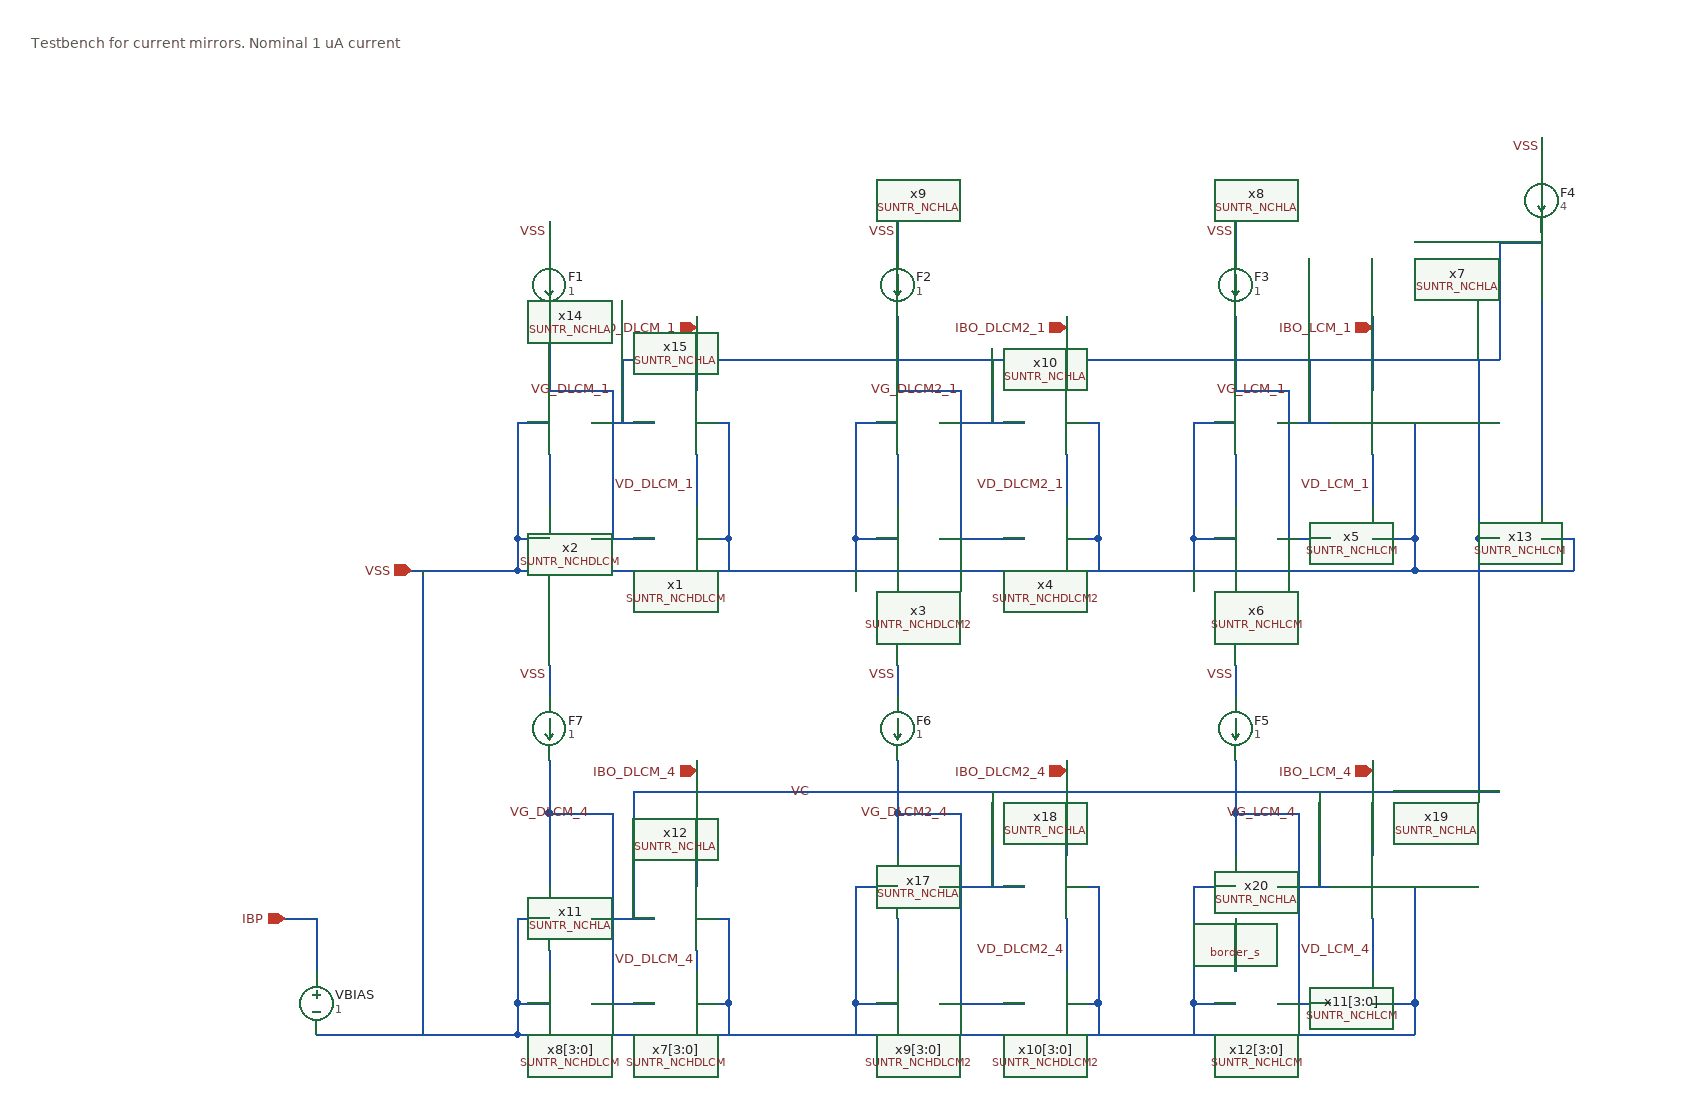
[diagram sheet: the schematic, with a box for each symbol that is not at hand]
v {xschem version=3.0.0 file_version=1.2 }
G {}
K {}
V {}
S {}
E {}
T {Testbench for current mirrors. Nominal 1 uA current} -580 -510 0 0 0.4 0.4 {}
N -120 -30 -90 -30 {
lab=VSS}
N -120 -30 -120 0 {
lab=VSS}
N -120 0 -90 -0 {
lab=VSS}
N -90 -0 50 0 {
lab=VSS}
N 50 0 240 0 {
lab=VSS}
N 200 -30 240 -30 {
lab=VSS}
N 200 -30 200 -0 {
lab=VSS}
N 50 -30 80 -30 {
lab=VSS}
N 80 -30 80 -0 {
lab=VSS}
N 240 0 400 0 {
lab=VSS}
N 400 0 560 0 {
lab=VSS}
N 560 0 690 0 {
lab=VSS}
N 520 -30 560 -30 {
lab=VSS}
N 520 -30 520 -0 {
lab=VSS}
N 400 -30 430 -30 {
lab=VSS}
N 430 -30 430 -0 {
lab=VSS}
N 280 -30 360 -30 {
lab=VG_DLCM2_1}
N 600 -30 650 -30 {
lab=VG_LCM_1}
N -50 -30 10 -30 {
lab=VG_DLCM_1}
N -220 0 -120 0 {
lab=VSS}
N -90 -110 -90 -60 {
lab=#net1}
N -90 -330 -90 -300 {
lab=VSS}
N 240 -110 240 -60 {
lab=#net2}
N 240 -330 240 -300 {
lab=VSS}
N 560 -110 560 -60 {
lab=#net3}
N 560 -330 560 -300 {
lab=VSS}
N 50 -110 50 -60 {
lab=VD_DLCM_1}
N 400 -110 400 -60 {
lab=VD_DLCM2_1}
N 690 -110 690 -60 {
lab=VD_LCM_1}
N 690 -30 730 -30 {
lab=VSS}
N 730 -30 730 -0 {
lab=VSS}
N 690 0 730 -0 {
lab=VSS}
N -120 410 -90 410 {
lab=VSS}
N -120 410 -120 440 {
lab=VSS}
N -120 440 -90 440 {
lab=VSS}
N -90 440 50 440 {
lab=VSS}
N 50 440 240 440 {
lab=VSS}
N 200 410 240 410 {
lab=VSS}
N 200 410 200 440 {
lab=VSS}
N 50 410 80 410 {
lab=VSS}
N 80 410 80 440 {
lab=VSS}
N 240 440 400 440 {
lab=VSS}
N 400 440 560 440 {
lab=VSS}
N 560 440 690 440 {
lab=VSS}
N 520 410 560 410 {
lab=VSS}
N 520 410 520 440 {
lab=VSS}
N 400 410 430 410 {
lab=VSS}
N 430 410 430 440 {
lab=VSS}
N 280 410 360 410 {
lab=VG_DLCM2_4}
N 300 380 300 410 {
lab=VG_DLCM2_4}
N 240 230 280 230 {
lab=VG_DLCM2_4}
N 600 410 650 410 {
lab=VG_LCM_4}
N 620 380 620 410 {
lab=VG_LCM_4}
N 560 230 600 230 {
lab=VG_LCM_4}
N -50 410 10 410 {
lab=VG_DLCM_4}
N -30 380 -30 410 {
lab=VG_DLCM_4}
N -90 230 -50 230 {
lab=VG_DLCM_4}
N -220 440 -120 440 {
lab=VSS}
N -90 180 -90 230 {
lab=VG_DLCM_4}
N -90 90 -90 120 {
lab=VSS}
N 240 180 240 230 {
lab=VG_DLCM2_4}
N 240 90 240 120 {
lab=VSS}
N 560 180 560 230 {
lab=VG_LCM_4}
N 560 90 560 120 {
lab=VSS}
N 50 180 50 230 {
lab=IBO_DLCM_4}
N 400 180 400 230 {
lab=IBO_DLCM2_4}
N 690 180 690 230 {
lab=IBO_LCM_4}
N 690 410 730 410 {
lab=VSS}
N 730 410 730 440 {
lab=VSS}
N 690 440 730 440 {
lab=VSS}
N -310 330 -310 380 {
lab=IBP}
N -340 330 -310 330 {
lab=IBP}
N -210 0 -210 440 {
lab=VSS}
N 600 -140 650 -140 {
lab=VC}
N 520 -140 560 -140 {
lab=VSS}
N 520 -140 520 -30 {
lab=VSS}
N 690 -140 730 -140 {
lab=VSS}
N 730 -140 730 -30 {
lab=VSS}
N -50 -140 10 -140 {
lab=VC}
N -120 -140 -90 -140 {
lab=VSS}
N -120 -140 -120 -30 {
lab=VSS}
N 50 -140 80 -140 {
lab=VSS}
N 80 -140 80 -30 {
lab=VSS}
N 200 -140 240 -140 {
lab=VSS}
N 200 -140 200 -30 {
lab=VSS}
N 400 -140 430 -140 {
lab=VSS}
N 430 -140 430 -30 {
lab=VSS}
N 280 -140 360 -140 {
lab=VC}
N -90 -170 -30 -170 {
lab=VG_DLCM_1}
N -30 -170 -30 -30 {
lab=VG_DLCM_1}
N 240 -170 300 -170 {
lab=VG_DLCM2_1}
N 300 -170 300 -30 {
lab=VG_DLCM2_1}
N 560 -170 610 -170 {
lab=VG_LCM_1}
N 610 -170 610 -30 {
lab=VG_LCM_1}
N 690 -240 690 -170 {
lab=IBO_LCM_1}
N 560 -240 560 -170 {
lab=VG_LCM_1}
N 400 -240 400 -170 {
lab=IBO_DLCM2_1}
N 240 -240 240 -170 {
lab=VG_DLCM2_1}
N 50 -240 50 -170 {
lab=IBO_DLCM_1}
N -90 -240 -90 -170 {
lab=VG_DLCM_1}
N 850 -410 850 -380 {
lab=VSS}
N 850 -30 880 -30 {
lab=VSS}
N 880 -30 880 -0 {
lab=VSS}
N 850 -0 880 -0 {
lab=VSS}
N 730 0 850 -0 {
lab=VSS}
N -20 -200 -20 -140 {
lab=VC}
N -20 -200 800 -200 {
lab=VC}
N 330 -200 330 -140 {
lab=VC}
N 630 -200 630 -140 {
lab=VC}
N 790 -200 790 -30 {
lab=VC}
N 800 -200 810 -200 {
lab=VC}
N 810 -270 810 -200 {
lab=VC}
N 850 -320 850 -300 {
lab=VC}
N 810 -310 810 -270 {
lab=VC}
N 810 -310 850 -310 {
lab=VC}
N 240 330 240 380 {
lab=#net4}
N 400 330 400 380 {
lab=VD_DLCM2_4}
N 200 300 240 300 {
lab=VSS}
N 200 300 200 410 {
lab=VSS}
N 400 300 430 300 {
lab=VSS}
N 430 300 430 410 {
lab=VSS}
N 280 300 360 300 {
lab=VC}
N 560 330 560 380 {
lab=#net5}
N 690 330 690 380 {
lab=VD_LCM_4}
N 600 300 650 300 {
lab=VC}
N 520 300 560 300 {
lab=VSS}
N 520 300 520 410 {
lab=VSS}
N 690 300 730 300 {
lab=VSS}
N 730 300 730 410 {
lab=VSS}
N -90 360 -90 380 {
lab=#net6}
N 50 360 50 380 {
lab=VD_DLCM_4}
N 50 330 80 330 {
lab=VSS}
N 80 330 80 410 {
lab=VSS}
N -120 330 -90 330 {
lab=VSS}
N -120 330 -120 410 {
lab=VSS}
N -90 230 -90 300 {
lab=VG_DLCM_4}
N -50 330 10 330 {
lab=VC}
N -30 230 -30 380 {
lab=VG_DLCM_4}
N -50 230 -30 230 {
lab=VG_DLCM_4}
N 50 230 50 300 {
lab=IBO_DLCM_4}
N 240 230 240 270 {
lab=VG_DLCM2_4}
N 300 230 300 380 {
lab=VG_DLCM2_4}
N 280 230 300 230 {
lab=VG_DLCM2_4}
N 400 230 400 270 {
lab=IBO_DLCM2_4}
N 620 230 620 380 {
lab=VG_LCM_4}
N 600 230 620 230 {
lab=VG_LCM_4}
N 560 230 560 270 {
lab=VG_LCM_4}
N 690 230 690 270 {
lab=IBO_LCM_4}
N -10 210 -10 330 {
lab=VC}
N -10 210 810 210 {
lab=VC}
N 790 -30 790 210 {
lab=VC}
N 640 210 640 300 {
lab=VC}
N 330 210 330 300 {
lab=VC}
N 850 -300 850 -220 {
lab=VC}
N 850 -220 850 -60 {
lab=VC}
N 790 -30 810 -30 {
lab=VC}
N -310 440 -220 440 {
lab=VSS}
C {SUN_TR_SKY130NM/SUNTR_NCHDLCM.sym} 10 -30 0 0 {name=x1 }
C {SUN_TR_SKY130NM/SUNTR_NCHDLCM.sym} -50 -30 0 1 {name=x2 }
C {SUN_TR_SKY130NM/SUNTR_NCHDLCM2.sym} 280 -30 0 1 {name=x3 }
C {SUN_TR_SKY130NM/SUNTR_NCHDLCM2.sym} 360 -30 0 0 {name=x4 }
C {SUN_TR_SKY130NM/SUNTR_NCHLCM.sym} 650 -30 0 0 {name=x5 }
C {SUN_TR_SKY130NM/SUNTR_NCHLCM.sym} 600 -30 0 1 {name=x6 }
C {devices/ipin.sym} -220 0 0 0 {name=p1 lab=VSS}
C {devices/lab_wire.sym} -90 -320 0 0 {name=l1 sig_type=std_logic lab=VSS}
C {devices/lab_wire.sym} 240 -320 0 0 {name=l2 sig_type=std_logic lab=VSS}
C {devices/lab_wire.sym} 560 -320 0 0 {name=l3 sig_type=std_logic lab=VSS}
C {devices/ipin.sym} 50 -230 1 0 {name=p2 lab=IBO_DLCM_1}
C {devices/ipin.sym} 400 -230 1 0 {name=p3 lab=IBO_DLCM2_1}
C {devices/ipin.sym} 690 -230 1 0 {name=p4 lab=IBO_LCM_1}
C {SUN_TR_SKY130NM/SUNTR_NCHDLCM.sym} 10 410 0 0 {name=x7[3:0]}
C {SUN_TR_SKY130NM/SUNTR_NCHDLCM.sym} -50 410 0 1 {name=x8[3:0]}
C {SUN_TR_SKY130NM/SUNTR_NCHDLCM2.sym} 280 410 0 1 {name=x9[3:0]}
C {SUN_TR_SKY130NM/SUNTR_NCHDLCM2.sym} 360 410 0 0 {name=x10[3:0]}
C {SUN_TR_SKY130NM/SUNTR_NCHLCM.sym} 650 410 0 0 {name=x11[3:0]}
C {SUN_TR_SKY130NM/SUNTR_NCHLCM.sym} 600 410 0 1 {name=x12[3:0]}
C {devices/lab_wire.sym} -90 100 0 0 {name=l4 sig_type=std_logic lab=VSS}
C {devices/lab_wire.sym} 240 100 0 0 {name=l5 sig_type=std_logic lab=VSS}
C {devices/lab_wire.sym} 560 100 0 0 {name=l6 sig_type=std_logic lab=VSS}
C {devices/ipin.sym} 50 190 1 0 {name=p6 lab=IBO_DLCM_4}
C {devices/ipin.sym} 400 190 1 0 {name=p7 lab=IBO_DLCM2_4}
C {devices/ipin.sym} 690 190 1 0 {name=p8 lab=IBO_LCM_4}
C {devices/cccs.sym} -90 -270 0 0 {name=F1 vnam=VBIAS value=1}
C {devices/vsource.sym} -310 410 0 0 {name=VBIAS value=1}
C {devices/cccs.sym} 240 -270 0 0 {name=F2 vnam=VBIAS value=1}
C {devices/cccs.sym} 560 -270 0 0 {name=F3 vnam=VBIAS value=1}
C {devices/cccs.sym} 560 150 0 0 {name=F5 vnam=VBIAS value=1}
C {devices/cccs.sym} 240 150 0 0 {name=F6 vnam=VBIAS value=1}
C {devices/cccs.sym} -90 150 0 0 {name=F7 vnam=VBIAS value=1}
C {devices/ipin.sym} -340 330 0 0 {name=p9 lab=IBP}
C {cborder/border_s.sym} 580 360 0 0 {}
C {SUN_TR_SKY130NM/SUNTR_NCHLA.sym} 650 -140 0 0 {name=x7 }
C {SUN_TR_SKY130NM/SUNTR_NCHLA.sym} 600 -140 0 1 {name=x8 }
C {SUN_TR_SKY130NM/SUNTR_NCHLA.sym} 280 -140 0 1 {name=x9 }
C {SUN_TR_SKY130NM/SUNTR_NCHLA.sym} 360 -140 0 0 {name=x10 }
C {SUN_TR_SKY130NM/SUNTR_NCHLA.sym} -50 330 0 1 {name=x11 }
C {SUN_TR_SKY130NM/SUNTR_NCHLA.sym} 10 330 0 0 {name=x12 }
C {devices/lab_wire.sym} 850 -400 0 0 {name=l7 sig_type=std_logic lab=VSS}
C {devices/cccs.sym} 850 -350 0 0 {name=F4 vnam=VBIAS value=4}
C {SUN_TR_SKY130NM/SUNTR_NCHLCM.sym} 810 -30 0 0 {name=x13 }
C {SUN_TR_SKY130NM/SUNTR_NCHLA.sym} 280 300 0 1 {name=x17 }
C {SUN_TR_SKY130NM/SUNTR_NCHLA.sym} 360 300 0 0 {name=x18 }
C {SUN_TR_SKY130NM/SUNTR_NCHLA.sym} 650 300 0 0 {name=x19 }
C {SUN_TR_SKY130NM/SUNTR_NCHLA.sym} 600 300 0 1 {name=x20 }
C {SUN_TR_SKY130NM/SUNTR_NCHLA.sym} -50 -140 0 1 {name=x14 }
C {SUN_TR_SKY130NM/SUNTR_NCHLA.sym} 10 -140 0 0 {name=x15 }
C {devices/lab_wire.sym} 160 210 0 0 {name=l8 sig_type=std_logic lab=VC}
C {devices/lab_wire.sym} -50 230 0 0 {name=l9 sig_type=std_logic lab=VG_DLCM_4}
C {devices/lab_wire.sym} 290 230 0 0 {name=l10 sig_type=std_logic lab=VG_DLCM2_4}
C {devices/lab_wire.sym} 620 230 0 0 {name=l11 sig_type=std_logic lab=VG_LCM_4}
C {devices/lab_wire.sym} 50 370 0 0 {name=l12 sig_type=std_logic lab=VD_DLCM_4}
C {devices/lab_wire.sym} 400 360 0 0 {name=l13 sig_type=std_logic lab=VD_DLCM2_4}
C {devices/lab_wire.sym} 690 360 0 0 {name=l14 sig_type=std_logic lab=VD_LCM_4}
C {devices/lab_wire.sym} -30 -170 0 0 {name=l15 sig_type=std_logic lab=VG_DLCM_1}
C {devices/lab_wire.sym} 300 -170 0 0 {name=l16 sig_type=std_logic lab=VG_DLCM2_1}
C {devices/lab_wire.sym} 610 -170 0 0 {name=l17 sig_type=std_logic lab=VG_LCM_1}
C {devices/lab_wire.sym} 690 -80 0 0 {name=l18 sig_type=std_logic lab=VD_LCM_1}
C {devices/lab_wire.sym} 400 -80 0 0 {name=l19 sig_type=std_logic lab=VD_DLCM2_1}
C {devices/lab_wire.sym} 50 -80 0 0 {name=l20 sig_type=std_logic lab=VD_DLCM_1}
